VERSION 5.8 ;
BUSBITCHARS "[]" ;
DIVIDERCHAR "/" ;
CLEARANCEMEASURE EUCLIDEAN ;

SITE coresite_DH_P
    SIZE 0.0450 BY 0.2880 ;
    CLASS CORE ;
    SYMMETRY X Y ;
END coresite_DH_P

SITE coresite_DH_N
    SIZE 0.0450 BY 0.2880 ;
    CLASS CORE ;
    SYMMETRY X Y ;
END coresite_DH_N

SITE coresite
    SIZE 0.0450 BY 0.1440 ;
    CLASS CORE ;
    SYMMETRY X Y ;
END coresite

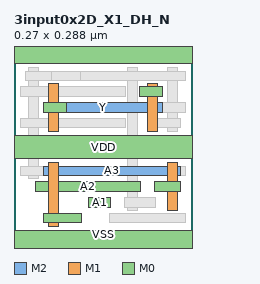
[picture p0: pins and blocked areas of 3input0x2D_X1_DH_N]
MACRO 3input0x2D_X1_DH_N
  CLASS CORE ;
  ORIGIN 0 0 ;
  FOREIGN 3input0x2D_X1_DH_N 0 0 ;
  SIZE 0.2700 BY 0.2880 ;
  SYMMETRY X Y ;
  SITE coresite_DH_N ;
  PIN A3
    DIRECTION INPUT ;
    USE SIGNAL ;
    PORT
      LAYER M2 ;
        RECT 0.0450 0.1150 0.2520 0.1010 ;
      LAYER M1 ;
        RECT 0.0525 0.1200 0.0675 0.0240 ;
        RECT 0.2325 0.1200 0.2475 0.0480 ;
      LAYER M0 ;
        RECT 0.0450 0.0430 0.1020 0.0290 ;
        RECT 0.2130 0.0910 0.2520 0.0770 ;
    END
  END A3
  PIN Y
    DIRECTION OUTPUT ;
    USE SIGNAL ;
    PORT
      LAYER M2 ;
        RECT 0.0450 0.2110 0.2250 0.1970 ;
      LAYER M1 ;
        RECT 0.0525 0.2400 0.0675 0.1680 ;
        RECT 0.2025 0.2400 0.2175 0.1680 ;
      LAYER M0 ;
        RECT 0.0450 0.2110 0.0795 0.1970 ;
        RECT 0.1905 0.2350 0.2250 0.2210 ;
    END
  END Y
  PIN A1
    DIRECTION INPUT ;
    USE SIGNAL ;
    PORT
      LAYER M0 ;
        RECT 0.1125 0.0670 0.1470 0.0530 ;
    END
  END A1
  PIN A2
    DIRECTION INPUT ;
    USE SIGNAL ;
    PORT
      LAYER M0 ;
        RECT 0.0330 0.0910 0.1920 0.0770 ;
    END
  END A2
  PIN VDD
    DIRECTION INOUT ;
    USE POWER ;
    SHAPE ABUTMENT ;
    PORT
      LAYER M0 ;
        RECT 0.0000 0.1260 0.2700 0.1620 ;
    END
  END VDD
  PIN VSS
    DIRECTION INOUT ;
    USE GROUND ;
    SHAPE ABUTMENT ;
    PORT
      LAYER M0 ;
        RECT 0.0000 -0.0180 0.2700 0.0180 ;
        RECT 0.0000 0.2700 0.2700 0.3060 ;
    END
  END VSS
  OBS
      LAYER V0 ;
        RECT 0.2330 0.1730 0.2470 0.1870 ;
        RECT 0.0230 0.1010 0.0370 0.1150 ;
        RECT 0.0230 0.2450 0.0370 0.2590 ;
        RECT 0.1730 0.0530 0.1870 0.0670 ;
        RECT 0.0530 0.0290 0.0670 0.0430 ;
        RECT 0.2330 0.0770 0.2470 0.0910 ;
        RECT 0.0530 0.1970 0.0670 0.2110 ;
        RECT 0.2030 0.2210 0.2170 0.2350 ;
      LAYER M1 ;
        RECT 0.0225 0.2640 0.0375 0.0960 ;
        RECT 0.1725 0.2640 0.1875 0.0480 ;
        RECT 0.2325 0.2640 0.2475 0.1680 ;
      LAYER V1 ;
        RECT 0.2330 0.2450 0.2470 0.2590 ;
        RECT 0.0230 0.2450 0.0370 0.2590 ;
        RECT 0.1730 0.2450 0.1870 0.2590 ;
        RECT 0.0530 0.1010 0.0670 0.1150 ;
        RECT 0.2330 0.1010 0.2470 0.1150 ;
        RECT 0.0530 0.1970 0.0670 0.2110 ;
        RECT 0.2030 0.1970 0.2170 0.2110 ;
      LAYER M2 ;
        RECT 0.0180 0.2450 0.2520 0.2590 ;
      LAYER M0 ;
        RECT 0.1455 0.0290 0.2595 0.0430 ;
        RECT 0.1680 0.0530 0.2145 0.0670 ;
        RECT 0.0105 0.1010 0.0450 0.1150 ;
        RECT 0.1455 0.1010 0.2595 0.1150 ;
        RECT 0.0105 0.1730 0.1695 0.1870 ;
        RECT 0.2130 0.1730 0.2520 0.1870 ;
        RECT 0.1005 0.1970 0.2595 0.2110 ;
        RECT 0.0105 0.2210 0.1695 0.2350 ;
        RECT 0.0180 0.2450 0.0570 0.2590 ;
        RECT 0.1005 0.2450 0.2595 0.2590 ;
  END
END 3input0x2D_X1_DH_N

END LIBRARY
